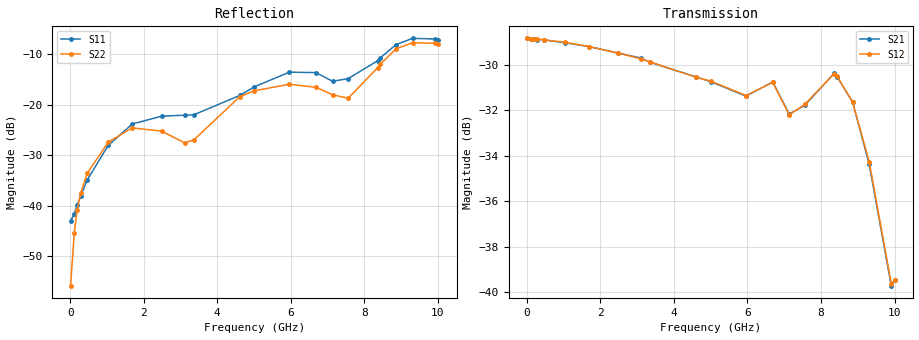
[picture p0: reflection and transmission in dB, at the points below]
! Device ID: PE43704
! Dir: z:\PE43704\PE43704_Char_1_20130516\PE43704\AMB\3p400V\28p00dB
! Serial: 14
! Insertion: A
! Impedance: 50 ohm
! Temp: Amb
! VDD: 3.400V
! Attenuation Step: 28.00dB
! IDD: 1.139780e-01mA
#  Hz  S  RI  R  50
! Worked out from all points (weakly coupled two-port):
!   401 points, 10 MHz to 10.01 GHz, reference 50 ohm
!   highest |S21| = -28.84 dB at 10 MHz (marker M1); lowest = -39.7 dB at 9.91 GHz (marker M2)
!   lowest |S11| = -43.1 dB at 10 MHz (marker M3), VSWR 1.01, Z = 50.7 + j0.0373 ohm
!   |S11| at or under -10 dB: start of sweep to 8.533 GHz
!   |S22| runs from -55.8 to -7.6 dB; largest |S21 - S12| = 0.00071
!   S11 on the Smith chart (normalised r, x): 10 MHz: 1.01, +0.00; 4.61 GHz: 0.80, +0.08; 8.435 GHz: 0.77, +0.48; 9.31 GHz: 0.51, +0.54; 10.01 GHz: 0.45, +0.33
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1e7  0.00702 0.000368  0.0361 -4.48e-05  0.0361 -0.00014  -0.00155 0.000448
1.1e8  0.00687 0.00469  0.036 -0.00103  0.036 -0.00104  -0.00153 0.00512
1.85e8  0.00603 0.00807  0.036 -0.00168  0.0359 -0.00169  -0.00206 0.00872
2.85e8  0.00401 0.0117  0.0358 -0.00254  0.0359 -0.00255  -0.00381 0.0127
4.6e8  -0.00111 0.0179  0.0356 -0.00408  0.0356 -0.00402  -0.00865 0.019
1.035e9  -0.031 0.0245  0.0342 -0.00876  0.0343 -0.00873  -0.0344 0.0251
1.685e9  -0.0637 0.00781  0.0319 -0.0135  0.0319 -0.0135  -0.0583 0.00817
2.485e9  -0.0754 -0.0154  0.028 -0.0184  0.028 -0.0184  -0.0542 -0.00715
3.11e9  -0.0771 -0.0152  0.0246 -0.0215  0.0245 -0.0214  -0.0418 0.0034
3.36e9  -0.0788 -0.0089  0.0228 -0.0224  0.0229 -0.0224  -0.043 0.012
4.61e9  -0.1115 0.0524  0.0157 -0.0252  0.0159 -0.025  -0.1022 0.0626
5.01e9  -0.1308 0.0739  0.0143 -0.0252  0.0143 -0.0253  -0.1229 0.0611
5.96e9  -0.1808 0.1063  0.00929 -0.0253  0.00926 -0.0254  -0.1486 0.0568
6.685e9  -0.1811 0.1012  0.00702 -0.0281  0.00717 -0.028  -0.1382 0.0544
7.135e9  -0.1478 0.0849  0.00223 -0.0245  0.0026 -0.0244  -0.1043 0.0691
7.56e9  -0.1223 0.1335  0.00268 -0.0256  0.00288 -0.0257  -0.0697 0.0924
8.36e9  -0.05 0.267  -0.0063 -0.0296  -0.00608 -0.0296  -0.0775 0.2186
8.435e9  -0.0503 0.2867  -0.00743 -0.0288  -0.00747 -0.0289  -0.0864 0.236
8.86e9  -0.0897 0.3822  -0.0133 -0.0225  -0.0131 -0.0226  -0.1433 0.3264
9.31e9  -0.1703 0.4198  -0.0124 -0.0145  -0.0128 -0.0145  -0.2275 0.3412
9.91e9  -0.2974 0.3339  -0.00348 -0.00973  -0.00357 -0.00981  -0.3452 0.2119
1.001e10  -0.3141 0.3022  -0.00179 -0.0105  -0.00216 -0.0104  -0.3585 0.1746
